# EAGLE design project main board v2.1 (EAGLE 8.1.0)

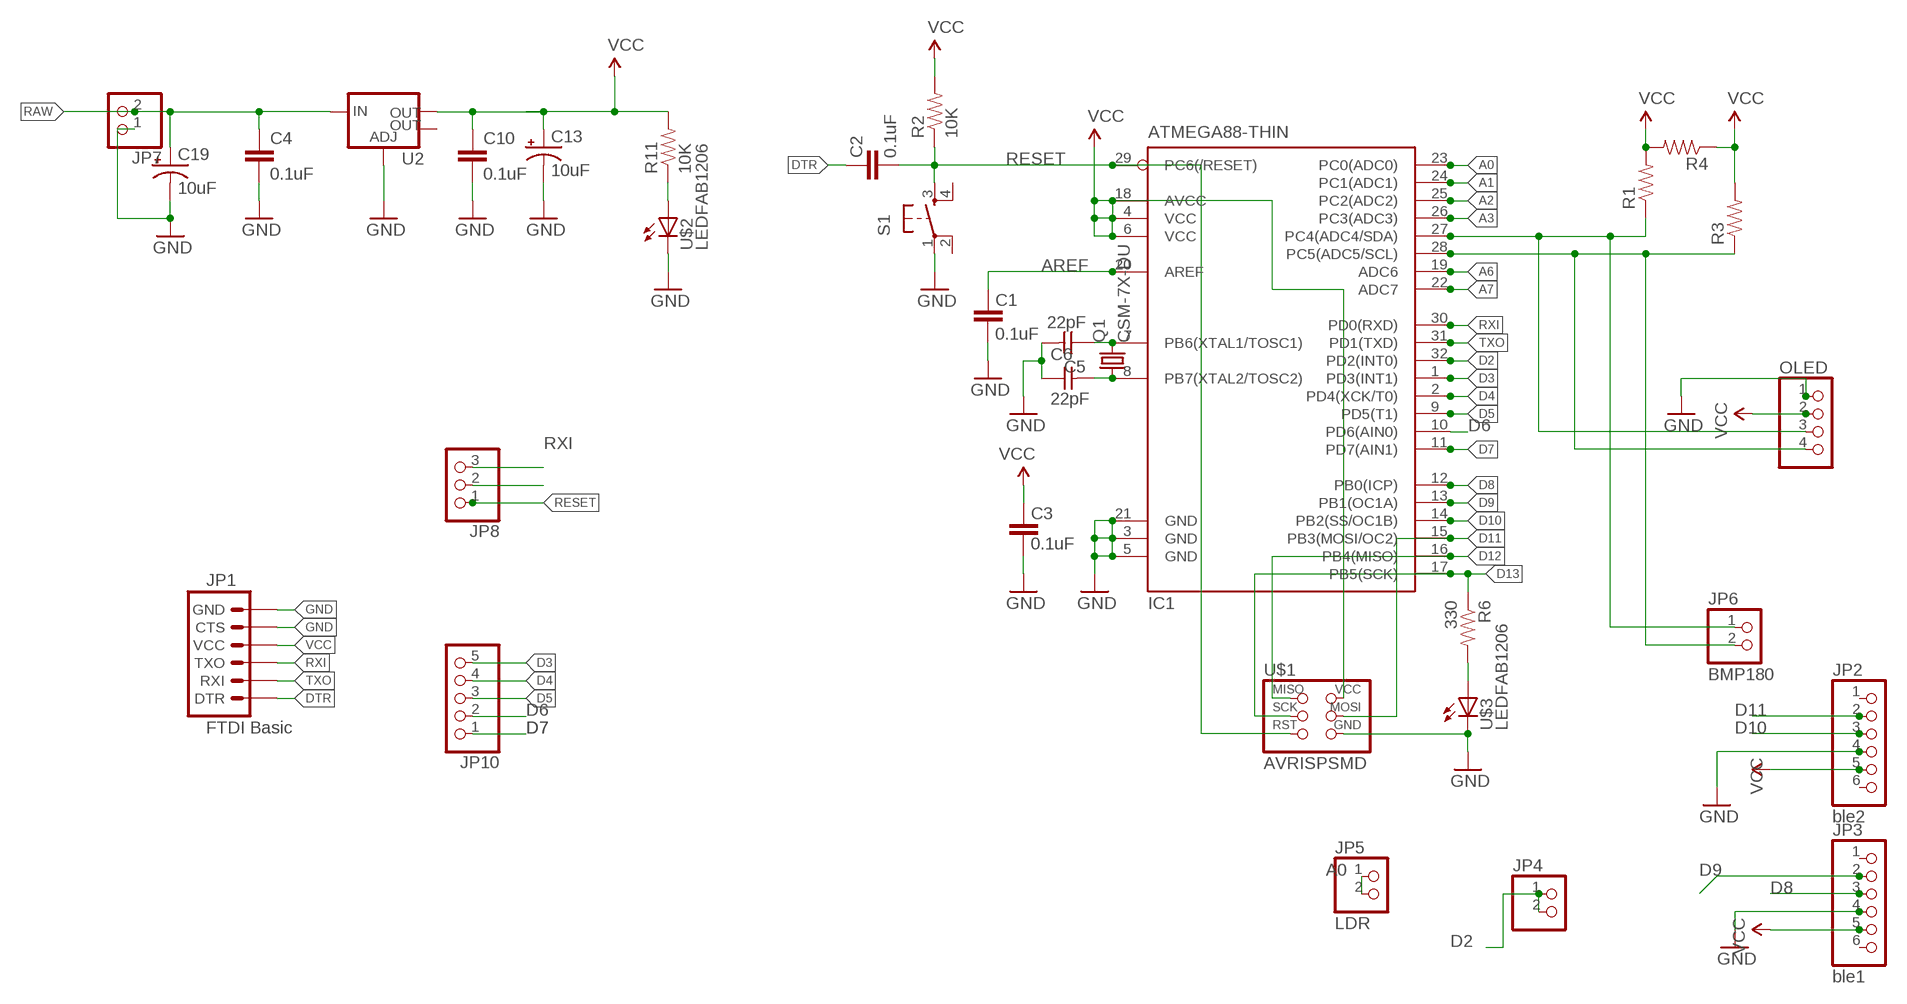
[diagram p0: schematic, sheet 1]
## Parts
C1  0.1uF  CAP1206  [1206]
C2  0.1uF  CAP1206  [1206]
C3  0.1uF  CAP1206  [1206]
C4  0.1uF  CAP1206  [1206]
C5  22pF  CAP-UNPOLARIZEDFAB  [C1206FAB]
C6  22pF  CAP-UNPOLARIZEDFAB  [C1206FAB]
C10  0.1uF  CAP1206  [1206]
C13  10uF  CAP_POL1206  [EIA3216]
C19  10uF  CAP_POL1206  [EIA3216]
IC1  ATMEGA88-THIN  [TQFP32-08THIN]
JP1  FTDI Basic  ARDUINO_SERIAL_PROGRAMLONGPADS  [1X06_LONGPADS]
JP2  ble2  PINHD-1X6  [1X06]
JP3  ble1  PINHD-1X6  [1X06]
JP4  PINHD-1X2  [1X02]
JP5  LDR  PINHD-1X2  [1X02]
JP6  BMP180  PINHD-1X2  [1X02]
JP7  PINHD-1X2  [1X02]
JP8  PINHD-1X3  [1X03]
JP10  PINHD-1X5  [1X05]
OLED  PINHD-1X4  [1X04]
Q1  CSM-7X-DU  [CSM-7X-DU]
R1  RESISTOR1206  [1206]
R2  10K  RESISTOR1206  [1206]
R3  RESISTOR1206  [1206]
R4  RESISTOR1206  [1206]
R6  330  RESISTOR1206  [1206]
R11  10K  RESISTOR1206  [1206]
S1  6MM_SWITCH6MM_SWITCH  [6MM_SWITCH]
U2  V_REG_LM1117SOT223  [SOT223]
U$1  AVRISPSMD  [2X03SMD]
U$2  LEDFAB1206  [LED1206FAB]
U$3  LEDFAB1206  [LED1206FAB]

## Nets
A0: IC1.23(PC0(ADC0)) JP5.1 JP5.2
A1: IC1.24(PC1(ADC1))
A2: IC1.25(PC2(ADC2))
A3: IC1.26(PC3(ADC3))
A4: IC1.27(PC4(ADC4/SDA)) JP6.1 OLED.3 R1.1
A5: IC1.28(PC5(ADC5/SCL)) JP6.2 OLED.4 R3.1
A6: IC1.19(ADC6)
A7: IC1.22(ADC7)
AREF: C1.2 IC1.20(AREF)
D2: IC1.32(PD2(INT0)) JP4.1 JP4.2
D3: IC1.1(PD3(INT1)) JP10.5
D4: IC1.2(PD4(XCK/T0)) JP10.4
D5: IC1.9(PD5(T1)) JP10.3
D6: IC1.10(PD6(AIN0)) JP10.2
D7: IC1.11(PD7(AIN1)) JP10.1
D8: IC1.12(PB0(ICP)) JP3.3
D9: IC1.13(PB1(OC1A)) JP3.2
D10: IC1.14(PB2(SS/OC1B)) JP2.3
D11: IC1.15(PB3(MOSI/OC2)) JP2.2 U$1.4(MOSI)
D12: IC1.16(PB4(MISO)) U$1.1(MISO)
D13: IC1.17(PB5(SCK)) R6.1 U$1.3(SCK)
DTR: C2.2 JP1.1(DTR)
GND [vcc]: C1.1 C3.1 C4.2 C5.2 C6.1 C10.2 C13.C(-) C19.C(-) IC1.3(GND) IC1.5(GND) IC1.21(GND) JP1.5(CTS) JP1.6(GND) JP2.4 JP3.4 JP7.1 OLED.1 S1.1(P) U2.1(ADJ) U$1.6(GND) U$2.2(C) U$3.2(C)
N$1: C6.2 IC1.8(PB7(XTAL2/TOSC2)) Q1.1
N$2: C5.1 IC1.7(PB6(XTAL1/TOSC1)) Q1.2
N$3: R11.1 U$2.1(A)
N$7: R6.2 U$3.1(A)
RAW [vcc]: C4.1 C19.A(+) JP7.2 U2.3(IN)
RESET: C2.1 IC1.29(PC6(/RESET)) JP8.1 R2.1 S1.3(S) U$1.5(RST)
RXI: IC1.30(PD0(RXD)) JP1.3(TXO) JP8.3
TXO: IC1.31(PD1(TXD)) JP1.2(RXI) JP8.2
VCC: C3.2 C10.1 C13.A(+) IC1.4(VCC) IC1.6(VCC) IC1.18(AVCC) JP1.4(VCC) JP2.5 JP3.5 OLED.2 R1.2 R2.2 R3.2 R4.1 R4.2 R11.2 U2.2(OUT) U$1.2(VCC)
Unconnected: JP2.1 JP2.6 JP3.1 JP3.6 S1.2(P1) S1.4(S1) U2.4(OUT)

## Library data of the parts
C1-C4 C10 = SparkFun:CAP: Capacitor
C5 C6 = fab:CAP-UNPOLARIZED
C13 C19 = SparkFun:CAP_POL: Capacitor Polarized
IC1 = fab:ATMEGA88-THIN
JP1 = SparkFun:ARDUINO_SERIAL_PROGRAM
JP2 JP3 = pinhead:PINHD-1X6: PIN HEADER
JP4-JP7 = pinhead:PINHD-1X2: PIN HEADER
JP8 = pinhead:PINHD-1X3: PIN HEADER
JP10 = pinhead:PINHD-1X5: PIN HEADER
OLED = pinhead:PINHD-1X4: PIN HEADER
Q1 = crystal:CSM-7X-DU: SMD CRYSTAL; OC_FARNELL: unknown; OC_NEWARK: unknown
R1-R4 R6 R11 = SparkFun:RESISTOR: Resistor
S1 = fab:6MM_SWITCH: OMRON SWITCH
U2 = fab:V_REG_LM1117: Voltage Regulator LM1117 Standard adjustable voltage regulator but in SMD form. Spark Fun Electronics SKU : COM-00595; PROD_ID: VREG-08170
U$1 = fab:AVRISP
U$2 U$3 = fab:LED: LED

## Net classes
0 default: width 0.203 mm
1 vcc: width 0.254 mm

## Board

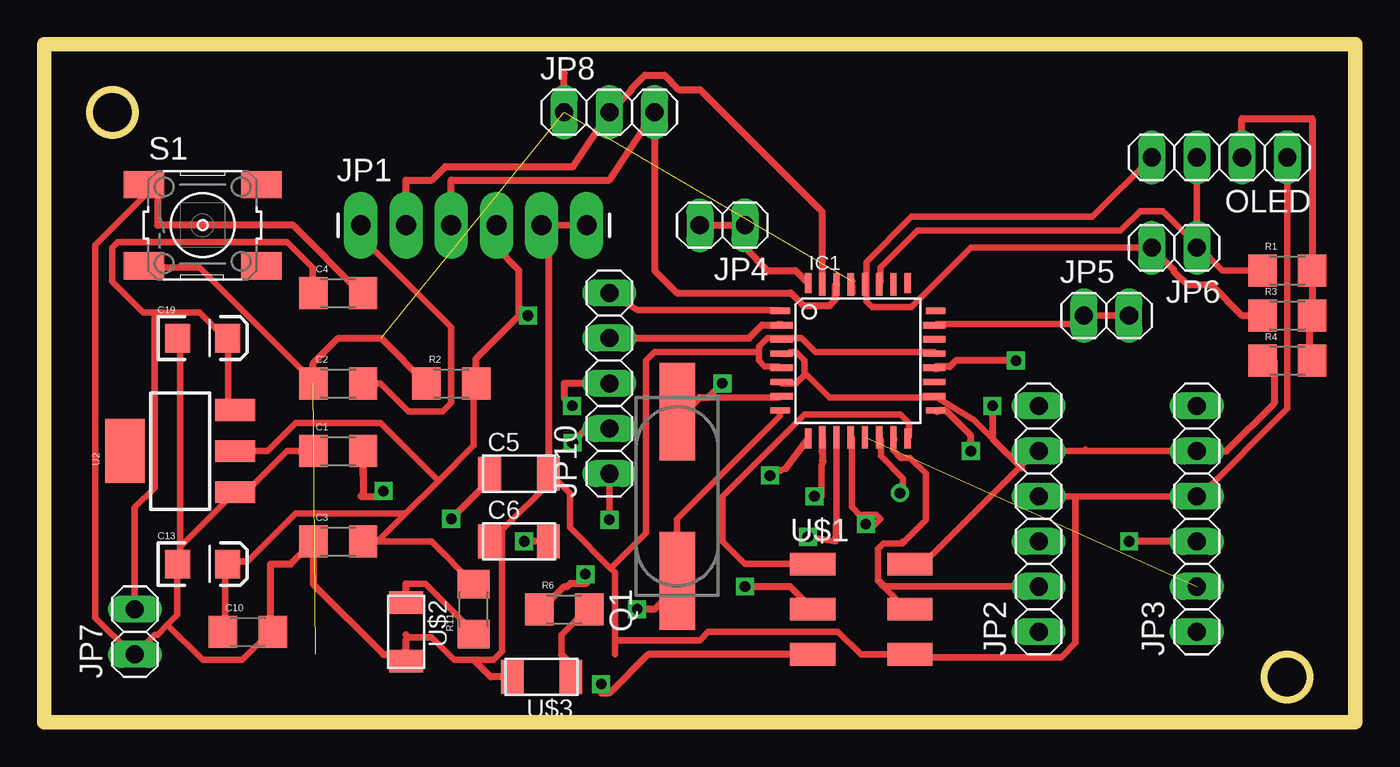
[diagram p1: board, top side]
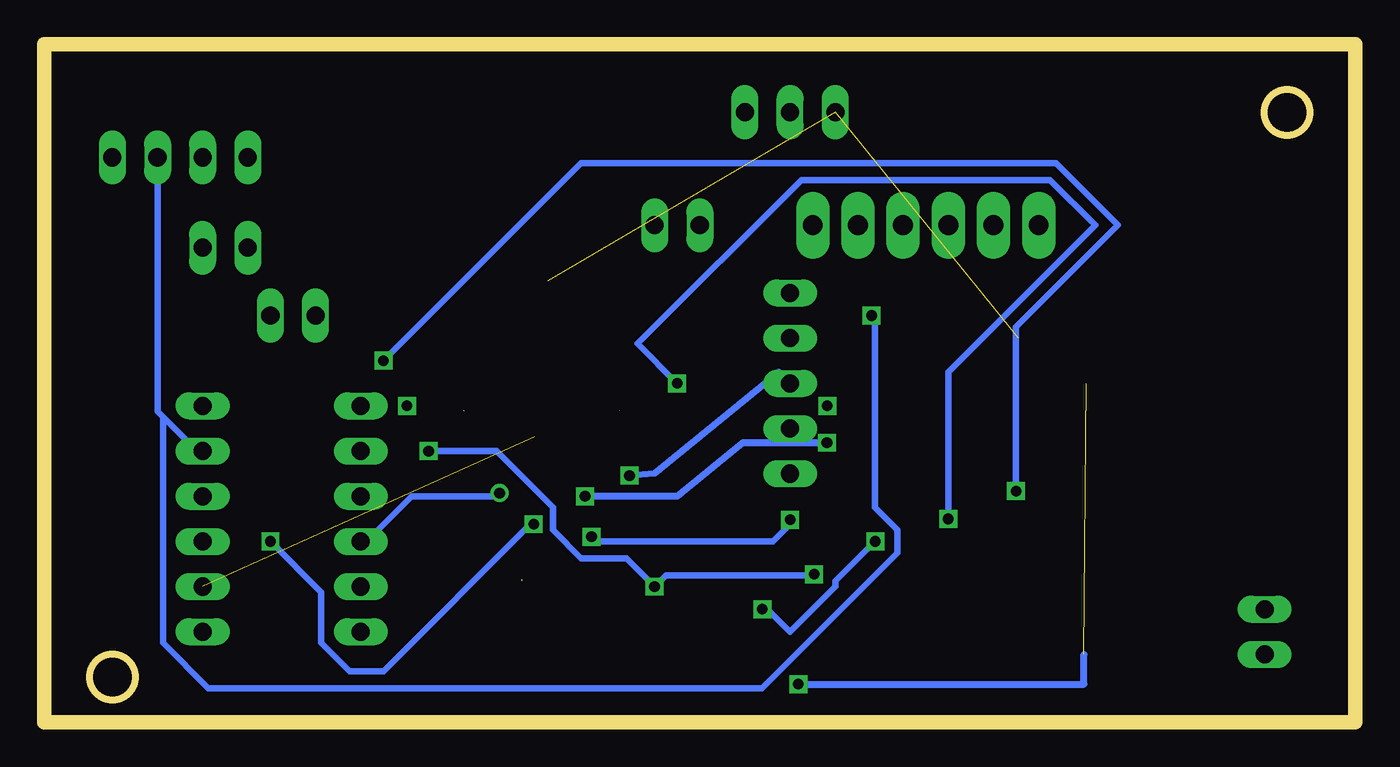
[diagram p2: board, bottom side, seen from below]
Size 73.66 x 38.1 mm. Coordinates in mm from the lower left corner, seen from the top.
Outline: 0,0 73.66,0 73.66,38.1 0,38.1 0,0
Outline: circle at 3.81,34.29 radius 1.27
Outline: circle at 69.85,2.54 radius 1.27
Copper layers (1*16): Top 0.035mm / dielectric 1.5mm / Bottom 0.035mm
Design rules "default *": minimum track width 14mil, minimum drill 32mil, track to track 14mil, track to pad 14mil, pad to pad 14mil, via to via 14mil, smd to smd 14mil, copper to edge 40mil, drill to drill 14mil, minimum pad ring 10mil, minimum via ring 8mil, stop-mask expansion 4mil, vias tented up to drill 0mil, thermal gap 10mil

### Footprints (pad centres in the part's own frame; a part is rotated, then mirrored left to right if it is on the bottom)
1206 = smd 1.6 x 1.8: 1 -1.4,0; 2 1.4,0
C1206FAB = smd 1.27 x 1.905: 1 -1.651,0; 2 1.651,0
EIA3216 = smd 1.4 x 1.6: A 1.4,0; C -1.4,0
TQFP32-08THIN = smd 1.118 x 0.356: 1 -4.369,2.8; 8 -4.369,-2.8; 17 4.369,-2.8; 24 4.369,2.8 | smd 1.27 x 0.356: 2 -4.293,2; 3 -4.293,1.2; 4 -4.293,0.4; 5 -4.293,-0.4; 6 -4.293,-1.2; 7 -4.293,-2; 18 4.293,-2; 19 4.293,-1.2; 20 4.293,-0.4; 21 4.293,0.4; 22 4.293,1.2; 23 4.293,2 | smd 0.356 x 1.118: 9 -2.8,-4.369; 16 2.8,-4.369; 25 2.8,4.369; 32 -2.8,4.369 | smd 0.356 x 1.27: 10 -2,-4.293; 14 1.2,-4.293; 15 2,-4.293; 26 2,4.293; 27 1.2,4.293; 31 -2,4.293 | smd 0.35 x 1.27: 11 -1.2,-4.293; 12 -0.4,-4.293; 13 0.4,-4.293; 28 0.4,4.293; 29 -0.4,4.293; 30 -1.2,4.293
1X06_LONGPADS = drill 1.118 pad 1.88 long: 1 0,0; 2 2.54,0; 3 5.08,0; 4 7.62,0; 5 10.16,0; 6 12.7,0
1X06 = drill 1.016 long: 1 -6.35,0; 2 -3.81,0; 3 -1.27,0; 4 1.27,0; 5 3.81,0; 6 6.35,0
1X02 = drill 1.016 long: 1 -1.27,0; 2 1.27,0
1X03 = drill 1.016 long: 1 -2.54,0; 2 0,0; 3 2.54,0
1X05 = drill 1.016 long: 1 -5.08,0; 2 -2.54,0; 3 0,0; 4 2.54,0; 5 5.08,0
1X04 = drill 1.016 long: 1 -3.81,0; 2 -1.27,0; 3 1.27,0; 4 3.81,0
CSM-7X-DU = smd 5.5 x 2: 1 -4.75,0; 2 4.75,0
6MM_SWITCH = smd 2.286 x 1.524: 1 -3.302,2.286; 2 3.302,2.286; 3 -3.302,-2.286; 4 3.302,-2.286
SOT223 = smd 1.219 x 2.235: 1 -2.311,-3.099; 2 0,-3.099; 3 2.311,-3.099 | smd 3.6 x 2.2: 4 0,3.099
2X03SMD = smd 2.54 x 1.27: 1 -2.54,2.54; 2 2.92,2.54; 3 -2.54,0; 4 2.92,0; 5 -2.54,-2.54; 6 2.92,-2.54
LED1206FAB = smd 1.27 x 1.905: 1 -1.651,0; 2 1.651,0

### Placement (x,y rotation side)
C1  16.51,15.24 0 top
C2  16.51,19.05 0 top
C3  16.51,10.16 0 top
C4  16.51,24.13 0 top
C5  26.67,13.97 0 top
C6  26.67,10.16 0 top
C10  11.43,5.08 0 top
C13  8.89,8.89 0 top
C19  8.89,21.59 0 top
IC1  45.72,20.32 0 top
JP1  17.78,27.94 0 top
JP2  55.88,11.43 90 top
JP3  64.77,11.43 90 top
JP4  38.1,27.94 180 top
JP5  59.69,22.86 0 top
JP6  63.5,26.67 180 top
JP7  5.08,5.08 90 top
JP8  31.75,34.29 0 top
JP10  31.75,19.05 90 top
OLED  66.04,31.75 180 top
Q1  35.56,12.7 90 top
R1  69.85,25.4 0 top
R2  22.86,19.05 0 top
R3  69.85,22.86 0 top
R4  69.85,20.32 0 top
R6  29.21,6.35 0 top
R11  24.13,6.35 90 top
S1  8.89,27.94 0 top
U2  7.62,15.24 90 top
U$1  45.72,6.35 0 top
U$2  20.32,5.08 270 top
U$3  27.94,2.54 180 top

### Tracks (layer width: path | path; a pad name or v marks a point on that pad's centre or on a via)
A0
  Top 0.356: IC1.23 50.16,22.38 57.94,22.38 JP5.1 JP5.2
A4
  Top 0.356: JP6.1 64.77,26.83 62.86,28.73 61.59,28.73 60.48,27.62 49.05,27.62 46.99,25.56 46.99,24.77 IC1.27 | R1.1 66.2,25.4 64.93,26.67 JP6.1 | JP6.1 OLED.3
A5
  Top 0.356: OLED.4 58.9,28.42 48.74,28.42 46.2,25.88 46.2,24.77 IC1.28 46.2,24.61 46.2,23.65 46.51,23.34 48.74,23.34 52.07,26.67 JP6.2
  Top 0.406: JP6.2 63.45,25.45 63.45,25.36 64.22,24.59 65.58,24.59 67.31,22.86 R3.1
AREF  (via drill 0.6)
  Top 0.406: 17.91,13.84 C1.2 17.91,12.83 17.78,12.7 19.05,12.7 v19.05,12.99 | IC1.20 50.12,19.86 | IC1.20 50.16,19.86 | IC1.20 50.08,19.98 50.88,19.98 51.22,20.32 v54.61,20.32
  Bottom 0.356: v19.05,12.99 19.05,22.22 13.33,27.94 16.83,31.43 43.5,31.43 v54.61,20.32
D2
  Top 0.356: IC1.32 42.86,24.77
  Top 0.406: JP4.2 JP4.1 39.37,26.67 40.64,25.4 42.21,25.4 IC1.32
D3
  Top 0.356: JP10.5 33.34,23.18 41.27,23.18 IC1.1
D4
  Top 0.406: JP10.4 39.6,21.59 40.34,22.33 41.13,22.33 41.2,22.35 41.21,22.35 41.23,22.36 41.39,22.36 IC1.2
D5  (via drill 0.6)
  Top 0.406: JP10.3 29.21,19.05 29.21,18.23 v29.66,17.78 | IC1.9 41.65,14.25 v40.77,13.86
  Bottom 0.356: JP10.3 32.39,19.68 39.37,13.97 v40.77,13.86
D6  (via drill 0.6)
  Top 0.356: 43.72,14.51 43.66,14.45 43.66,12.7
  Top 0.406: 43.72,14.51 43.72,14.7 | IC1.10 43.72,15.24 | 43.72,15.24 43.72,14.7 | 43.76,14.66 43.72,14.7 | JP10.2 30.48,16.51 v29.68,15.71 29.32,15.35 | 43.68,15.24 43.72,15.24 | 43.66,12.7 v43.27,12.7
  Bottom 0.406: v29.68,15.71 34.42,15.71 38.1,12.7 v43.27,12.7
D7  (via drill 0.6)
  Top 0.356: IC1.11 44.52,11.5 44.45,10.16 v42.92,10.42 | JP10.1 v31.75,11.38
  Bottom 0.356: v42.92,10.42 42.86,10.16 32.7,10.16 31.75,11.11 v31.75,11.38
D8  (via drill 0.6)
  Top 0.356: IC1.12 45.38,15.96 45.38,12.09 45.82,11.66 46.76,11.66 46.99,11.43 46.69,11.13 v46.16,11.13
  Top 0.406: JP3.3 v60.96,10.16
  Bottom 0.356: v60.96,10.16 58.1,7.3 58.1,4.45 56.52,2.86 54.61,2.86 46.36,11.11 v46.16,11.13
D9  (1 unrouted)
D10  (via drill 0.6)
  Top 0.356: IC1.14 47.01,15.81 47.01,14.97 48.26,13.71 48.26,12.7 v48.08,12.88
  Bottom 0.356: JP2.3 55.56,10.16 53.02,12.7 48.26,12.7 v48.08,12.88
D11  (1 unrouted)
  Top 0.356: 47.23,7.54 48.42,6.35 U$1.4 | 47.23,7.54 46.83,7.94 | 47.78,15.88 IC1.15 47.72,15.26 48.12,14.86 48.64,14.86 49.53,13.97 49.53,11.38 48.21,10.06 | JP2.2 47.31,7.62 47.23,7.54 | 47.07,7.7 47.1,7.77 46.84,8.03 46.84,9.75 47.15,10.06 48.21,10.06 | 48.21,10.06 48.26,10.16
D12
  Top 0.356: IC1.16 48.58,16.03 48.58,16.83 48.1,17.3 42.7,17.3 38.1,12.7 38.1,10.16 39.37,8.89 U$1.1
D13  (via drill 0.6)  (1 unrouted)
  Top 0.406: R6.1 27.94,6.35 29.21,7.62 29.39,7.62 29.58,7.81 30.48,7.81 30.48,8.24 v30.4,8.32 | v39.37,7.62 41.91,7.62 U$1.3 | v52.07,15.24 52.07,16.1 50.65,17.52 50.31,17.52 50.16,17.46 50.08,17.49
  Bottom 0.356: v30.4,8.32 30.48,8.26 38.73,8.26 v39.37,7.62 40.96,9.21 43.5,9.21 45.09,10.79 45.09,12.06 48.26,15.24 v52.07,15.24
DTR
  Top 0.356: C2.2 18.89,19.05 20.48,17.46 22.38,17.46 22.86,17.94 22.86,22.22 17.78,27.3 JP1.1
GND
  Top 0.356: 57.94,12.7 JP3.4 64.93,12.7 69.85,17.62 OLED.1 | 57.94,12.7 JP2.4 | 15.08,10.16 C3.1 | 12.86,5.08 C10.2 | 7.62,9.84 7.62,8.89 C13.C 7.46,8.73 7.46,6.03 6.91,5.48 | 7.62,9.84 10.64,12.86 U2.1 10.79,13.02 11.43,13.02 13.65,15.24 C1.1 | 7.62,9.84 7.62,21.59 C19.C | 6.91,5.48 6.35,4.92 6.19,4.92 JP7.1 4.92,3.81 2.86,5.87 2.86,26.83 5.87,29.84 S1.1 | 12.7,5.08 11.11,3.49 8.89,3.49 6.91,5.48 | 40.16,20.8 40.16,21.11 40.64,21.59 41.27,21.59 IC1.3 41.43,21.59 42.55,21.59 43.34,20.8 50.01,20.8 IC1.21 | 40.16,20.8 40.16,20.32 40.48,20 41.27,20 IC1.5 | JP1.6 JP1.5 28.42,27.78 | 32.07,4.6 32.07,8.41 31.83,8.65 | 32.07,4.6 32.07,3.81 | 31.83,8.65 29.53,10.95 29.53,12.86 28.42,13.97 C5.2 | 25.64,10.72 28.58,13.65 C5.2 | 25.64,10.72 25.08,10.16 C6.1 | 32.07,4.6 36.83,4.6 37.31,5.08 44.61,5.08 45.88,3.81 U$1.6 48.58,3.65 57.15,3.65 57.94,4.45 57.94,12.7 | 28.42,14.13 C5.2 | 40.16,20.8 34.29,20.8 33.81,20.32 33.81,10.64 31.83,8.65 | 20.48,4.76 21.75,4.76 23.02,3.49 24.13,3.49 25.24,3.49 25.72,3.97 25.72,10.64 25.64,10.72
  Top 0.406: C4.2 17.78,24.13 13.97,27.94 6.35,27.94 6.35,30.23 | S1.1 6.35,30.23 | 6.35,30.23 6.35,30.48 | U$3.2 25.08,2.54 24.13,3.49 | 20.32,4.92 20.48,4.76 20.32,4.6 U$2.2 19.94,3.81 19.05,3.81 15.11,7.75 C3.1 13.84,8.89 12.7,8.89 12.7,5.08 C10.2 | JP1.5 28.32,27.94 C5.2
N$1  (via drill 0.6)  (1 unrouted)
  Top 0.356: 41.27,17.46 IC1.8 | 35.56,8.1 Q1.1 35.56,11.43 41.35,17.22 IC1.8
  Top 0.406: Q1.1 35.56,7.62 34.29,6.35 v33.31,6.35 33.02,6.35 | C6.2 v26.96,10.16 26.67,10.16
  Bottom 0.356: v26.96,10.16 26.99,10.16 29.21,7.94 29.21,7.62 31.75,5.08 33.02,6.35 v33.31,6.35
N$2  (via drill 0.6)
  Top 0.356: 36.83,18.26 41.27,18.26 IC1.7
  Top 0.406: C5.1 25.02,13.59 v22.86,11.43 | Q1.2 36.02,17.45 36.83,18.26 37.31,18.26 v38.1,19.05
  Bottom 0.356: v22.86,11.43 22.86,19.68 14.6,27.94 17.15,30.48 31.12,30.48 40.32,21.27 v38.1,19.05
  Bottom 0.406: v38.1,19.05
N$3
  Top 0.356: 20.32,7.78 21.43,7.78 24.13,5.08 R11.1
  Top 0.406: U$2.1 20.32,7.78
N$7
  Top 0.356: 29.05,3.81 29.05,4.92 30.48,6.35 R6.2
  Top 0.406: U$3.1 29.59,3.27 29.05,3.81
RAW
  Top 0.356: U2.3 10.64,17.62 10.32,17.94 10.32,21.59 C19.A 10.16,21.59 8.73,23.02 6.19,23.02 | 6.19,23.02 5.56,23.02 3.81,24.77 3.81,26.67 4.13,26.99 13.65,26.99 15.08,25.56 15.08,24.13 C4.1 | JP7.2 5.08,12.06 6.19,13.18 6.19,23.02
RESET  (via drill 0.6)  (3 unrouted)
  Top 0.356: S1.3 5.71,25.56 8.73,25.56 15.08,19.21 C2.1
  Top 0.406: C2.1 15.11,20.19 16.51,21.59 18.92,21.59 R2.1 | 45.33,24.67 45.39,24.79 45.33,24.67 | 45.33,24.67 45.34,24.63 IC1.29 | 45.33,24.67 45.37,24.52 45.36,24.37 45.39,24.34 45.39,24.13 | JP8.1 29.21,36.47 | U$1.5 33.93,3.81 31.75,1.63 31.29,1.63 v31.29,2.13
  Bottom 0.406: v31.29,2.13 15.24,2.13 15.24,3.81
RXI
  Top 0.406: JP1.3 22.86,30.48 31.75,30.48 JP8.3 34.29,25.4 35.56,24.13 41.95,24.13 42.66,23.42 44.13,23.42 44.46,23.75 44.46,24.55 IC1.30
TXO
  Top 0.406: 20.32,29.21 JP1.2 20.32,30.48 21.78,30.48 22.54,31.24 29.72,31.24 JP8.2 32.97,35.51 32.97,35.6 33.44,36.07 33.74,36.37 34.84,36.37 35.65,35.56 36.83,35.56 43.72,28.67 IC1.31
VCC  (via drill 0.6)
  Top 0.356: 42.7,19.53 42.23,19.05 41.43,19.05 IC1.6 | 42.7,19.53 42.7,20.32 42.23,20.8 41.91,20.8 | 42.7,19.53 42.86,19.53 44.13,18.26 50.01,18.26 IC1.18 50.16,18.26 52.23,16.99 54.85,14.37 | U$1.2 49.37,8.89 54.85,14.37 | 54.85,14.37 55.72,15.24 JP2.5 58.42,15.24 58.5,15.32 58.58,15.24 JP3.5 | 54.93,14.29 54.85,14.37 | C10.1 10.16,5.08 10.16,8.89 C13.A 10.32,9.05 11.43,9.05 14.13,11.75 20.16,11.75 20.24,11.67 | 18.89,10.16 21.75,10.16 24.13,7.78 R11.2 | 18.89,10.16 C3.2 | 20.24,11.67 18.89,10.32 18.89,10.16 | 20.24,11.67 22.15,13.57 | 22.15,13.57 24.13,15.56 24.13,19.05 R2.2 | U2.2 12.54,15.24 14.13,16.83 18.89,16.83 22.15,13.57
  Top 0.406: OLED.2 67.31,33.93 71.25,33.93 R1.2 R3.2 71.12,22.86 71.12,20.32 R4.2 | JP3.5 66.43,15.24 69.11,17.93 69.11,20.32 R4.1 | 24.26,19.18 R2.2 24.26,20.45 26.67,22.86 | IC1.4 41.83,20.72 41.91,20.8 | 26.67,22.86 26.67,25.4 25.4,26.67 JP1.4 | 26.67,22.86 v27.17,22.86 | v53.29,17.78 53.29,15.93 54.93,14.29
  Bottom 0.356: OLED.2 67.31,17.46 66.99,17.14 | 66.99,17.14 65.09,15.24 JP3.5 | 66.99,17.14 66.99,4.45 64.45,1.91 33.34,1.91 25.72,9.53 25.72,10.79 26.99,12.06 26.99,22.86 v27.17,22.86
  Bottom 0.406: 53.34,17.78 v53.29,17.78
